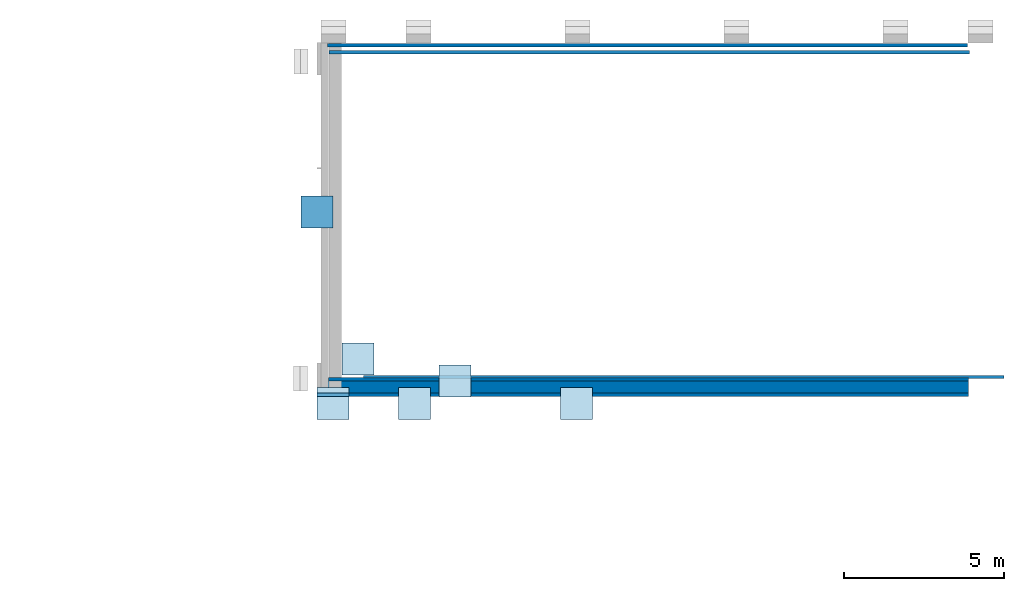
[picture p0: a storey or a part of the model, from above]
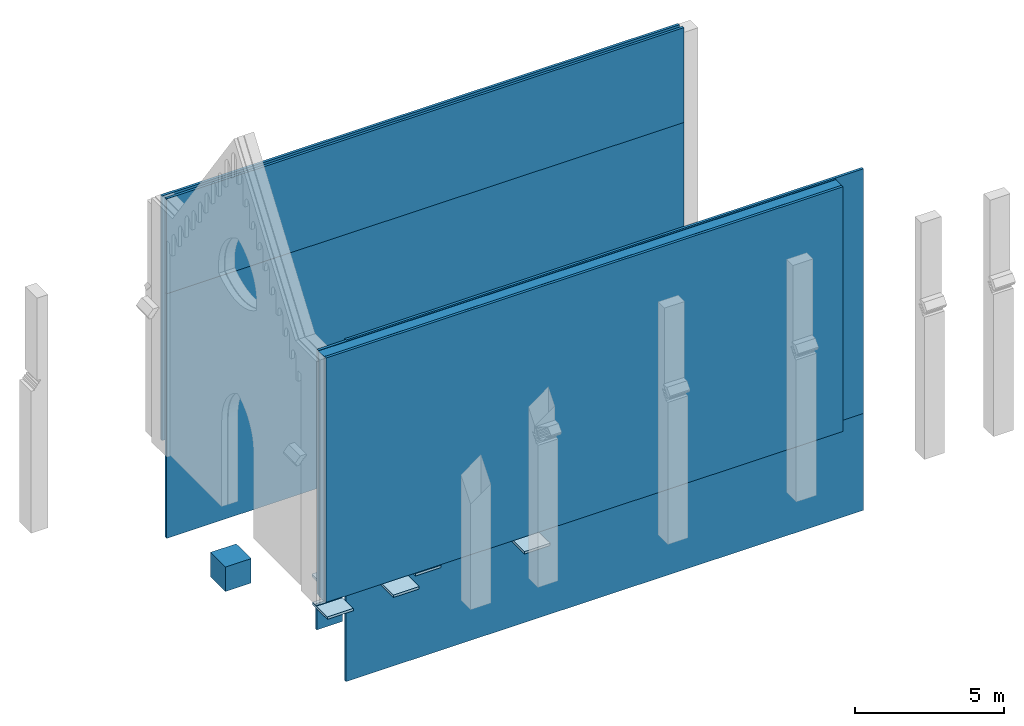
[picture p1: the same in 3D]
Properties of the parts of a building model (IFC4)

# File
Description: ViewDefinition[DesignTransferView]
File name: church.ifc
Time: 2024-10-19T21:49:25+02:00
Written by: IfcOpenShell v0.7.0-c7830e9e5
Made in: BlenderBIM 0.0.240602-47704b1
Authorization: Nobody

# IfcSlab: floor1, floor_finish_01
Type - PredefinedType: FLOOR; Material: render 0.1 m
Type - EPset_Parametric - LayerSetDirection: AXIS3
EPset_Parametric - Engine: BlenderBIM.DumbLayer3

# IfcSlab: plinth profile (4)
Type - PredefinedType: FLOOR; Material: render 0.1 m
Type - EPset_Parametric - LayerSetDirection: AXIS3
EPset_Parametric - Engine: BlenderBIM.DumbLayer3

# IfcWall (34)
Name | PredefinedType
Buttress_moulding_west_01 | SOLIDWALL
Buttress_west_01 | SOLIDWALL
Wall._west_core | SOLIDWALL | EPset_Parametric - Engine: BlenderBIM.DumbLayer2; Qto_WallBaseQuantities - Length: 20 m; Width: 0.38 m; Height: 10 m; GrossFootprintArea: 7.6 m2; NetFootprintArea: 7.6 m2; GrossSideArea: 200 m2; NetSideArea: 200 m2; GrossVolume: 76 m3; NetVolume: 76 m3
Buttress_moulding_east_01 | SOLIDWALL
Wall_east_finish | EPset_Parametric - Engine: BlenderBIM.DumbLayer2; Material: render 0.1 m
Buttress_east_01 | SOLIDWALL
wall_north_face_2 | SOLIDWALL
wall_north_core | SOLIDWALL
Wall_north_face_1 | SOLIDWALL
Buttress_north_01 | SOLIDWALL
Buttress_moulding_north_01 | SOLIDWALL
Buttress_north_01.001 | SOLIDWALL
Buttress_moulding_north_02 | SOLIDWALL
Wall_east_finish_
Buttress_moulding_west_02 | SOLIDWALL
Buttress_west_02 | SOLIDWALL
Buttress_moulding_west_03 | SOLIDWALL
Buttress_west_03 | SOLIDWALL
Buttress_moulding_west_04 | SOLIDWALL
Buttress_west_04 | SOLIDWALL
Buttress_moulding_west_05 | SOLIDWALL
Buttress_west_05 | SOLIDWALL
Buttress_moulding_west_06 | SOLIDWALL
Buttress_west_06 | SOLIDWALL
Buttress_east_02 | SOLIDWALL
Buttress_moulding_east_02 | SOLIDWALL
Buttress_east_03 | SOLIDWALL
Buttress_moulding_east_03 | SOLIDWALL
Buttress_east_04 | SOLIDWALL
Buttress_moulding_east_04 | SOLIDWALL
Buttress_east_05 | SOLIDWALL
Buttress_moulding_east_05 | SOLIDWALL
Buttress_east_06 | SOLIDWALL
Buttress_moulding_east_06 | SOLIDWALL

# IfcWall: bwk1 (8)
Type - PredefinedType: SOLIDWALL; Material: render 0.1 m
Type - EPset_Parametric - LayerSetDirection: AXIS2
EPset_Parametric - Engine: BlenderBIM.DumbLayer2
Name
Wall_west_facing
Wall_west_finish
Wall_east_facing
2 x Wall_east_core
2 x Wall_west_finish.001
Wall_west_plinth_01

# IfcWall: rubble, Wall
Type - PredefinedType: SOLIDWALL

# IfcWallType, no part of this type: sandstone
PredefinedType: SOLIDWALL; Material: render 0.1 m
EPset_Parametric - LayerSetDirection: AXIS2
